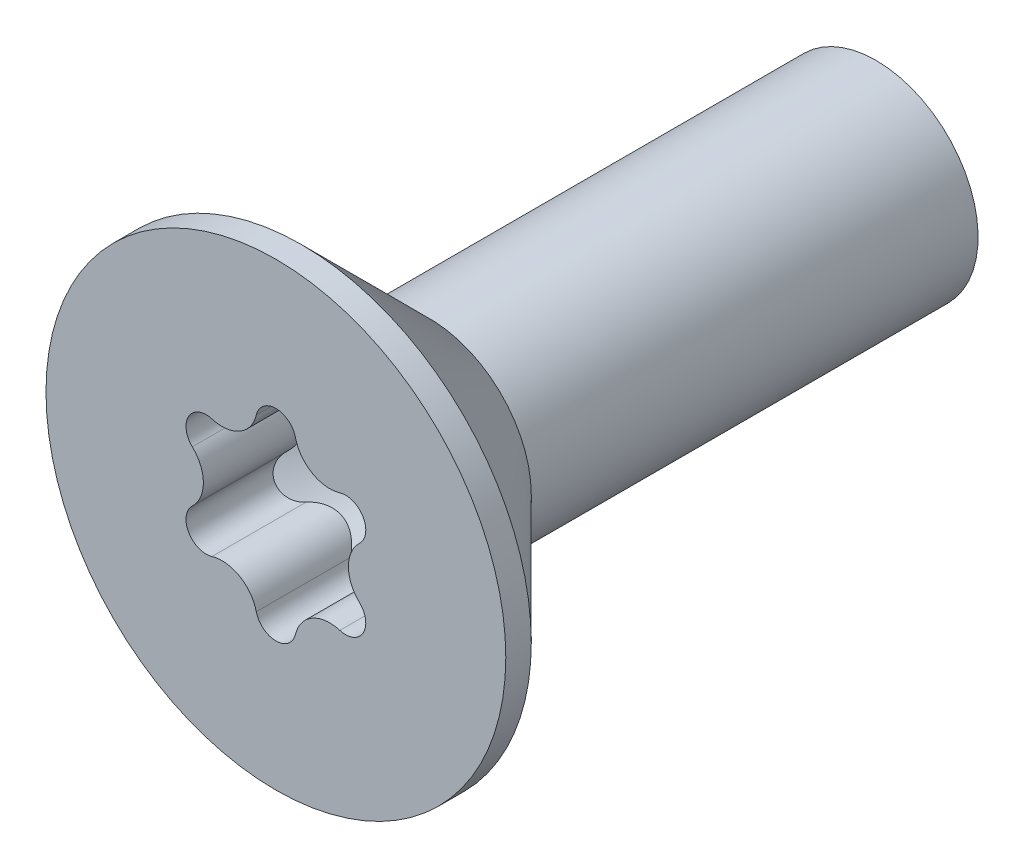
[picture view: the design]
ISO-10303-21;
HEADER;
FILE_DESCRIPTION(('STEP AP214'),'2;1');
FILE_NAME('part.step','',(''),(''),'','','');
FILE_SCHEMA(('AUTOMOTIVE_DESIGN { 1 0 10303 214 1 1 1 1 }'));
ENDSEC;
DATA;
#1=APPLICATION_CONTEXT('core data for automotive mechanical design processes');
#2=APPLICATION_PROTOCOL_DEFINITION('international standard','automotive_design',2000,#1);
#3=PRODUCT_CONTEXT('',#1,'mechanical');
#4=PRODUCT('Part','Part','',(#3));
#5=PRODUCT_RELATED_PRODUCT_CATEGORY('part','',(#4));
#6=PRODUCT_DEFINITION_FORMATION('','',#4);
#7=PRODUCT_DEFINITION_CONTEXT('part definition',#1,'design');
#8=PRODUCT_DEFINITION('design','',#6,#7);
#9=PRODUCT_DEFINITION_SHAPE('','',#8);
#10=(LENGTH_UNIT() NAMED_UNIT(*) SI_UNIT(.MILLI.,.METRE.));
#11=(NAMED_UNIT(*) PLANE_ANGLE_UNIT() SI_UNIT($,.RADIAN.));
#12=(NAMED_UNIT(*) SI_UNIT($,.STERADIAN.) SOLID_ANGLE_UNIT());
#13=UNCERTAINTY_MEASURE_WITH_UNIT(LENGTH_MEASURE(1.E-05),#10,'distance_accuracy_value','');
#14=(GEOMETRIC_REPRESENTATION_CONTEXT(3) GLOBAL_UNCERTAINTY_ASSIGNED_CONTEXT((#13)) GLOBAL_UNIT_ASSIGNED_CONTEXT((#10,
#11,#12)) REPRESENTATION_CONTEXT('',''));
#15=CARTESIAN_POINT('',(0.,0.,0.));
#16=DIRECTION('',(0.,0.,1.));
#17=DIRECTION('',(1.,0.,0.));
#18=AXIS2_PLACEMENT_3D('',#15,#16,#17);
#19=CARTESIAN_POINT('',(0.,0.,-2.87669972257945));
#20=DIRECTION('',(0.,0.,1.));
#21=DIRECTION('',(1.,0.,0.));
#22=AXIS2_PLACEMENT_3D('',#19,#20,#21);
#23=CONICAL_SURFACE('',#22,0.,1.02974425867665);
#24=CARTESIAN_POINT('',(0.,0.,-2.87669972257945));
#25=VERTEX_POINT('',#24);
#26=VERTEX_LOOP('',#25);
#27=FACE_BOUND('',#26,.T.);
#28=CARTESIAN_POINT('',(-0.384291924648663,-1.67134978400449,-1.84624734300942));
#29=CARTESIAN_POINT('',(-0.39260566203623,-1.63624557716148,-1.86565158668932));
#30=CARTESIAN_POINT('',(-0.403779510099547,-1.6013398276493,-1.88448405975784));
#31=CARTESIAN_POINT('',(-0.432157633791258,-1.53253400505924,-1.92005518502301));
#32=CARTESIAN_POINT('',(-0.449412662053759,-1.49864508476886,-1.93677455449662));
#33=CARTESIAN_POINT('',(-0.486363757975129,-1.43917197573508,-1.96402328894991));
#34=CARTESIAN_POINT('',(-0.505018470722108,-1.41321088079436,-1.97512558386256));
#35=CARTESIAN_POINT('',(-0.546368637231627,-1.36355413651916,-1.99422986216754));
#36=CARTESIAN_POINT('',(-0.569051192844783,-1.33985161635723,-2.00224149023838));
#37=CARTESIAN_POINT('',(-0.618391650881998,-1.2952919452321,-2.01447304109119));
#38=CARTESIAN_POINT('',(-0.6450836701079,-1.27446248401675,-2.01865799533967));
#39=CARTESIAN_POINT('',(-0.70148406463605,-1.23683559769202,-2.02256671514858));
#40=CARTESIAN_POINT('',(-0.731191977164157,-1.22003755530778,-2.02229116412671));
#41=CARTESIAN_POINT('',(-0.788409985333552,-1.19301747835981,-2.01765359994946));
#42=CARTESIAN_POINT('',(-0.81569849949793,-1.1822223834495,-2.01383140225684));
#43=CARTESIAN_POINT('',(-0.870881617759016,-1.16428859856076,-2.00322990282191));
#44=CARTESIAN_POINT('',(-0.898776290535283,-1.15715032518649,-1.99645026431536));
#45=CARTESIAN_POINT('',(-0.955959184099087,-1.14617507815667,-1.98005186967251));
#46=CARTESIAN_POINT('',(-0.985245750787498,-1.14252551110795,-1.97030570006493));
#47=CARTESIAN_POINT('',(-1.04329748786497,-1.13893373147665,-1.94874156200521));
#48=CARTESIAN_POINT('',(-1.07206196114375,-1.13899615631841,-1.93692102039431));
#49=CARTESIAN_POINT('',(-1.12719729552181,-1.14246664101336,-1.91242202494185));
#50=CARTESIAN_POINT('',(-1.15361466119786,-1.14569954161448,-1.89982077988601));
#51=CARTESIAN_POINT('',(-1.2053168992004,-1.15501804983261,-1.87366684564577));
#52=CARTESIAN_POINT('',(-1.23060610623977,-1.16109147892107,-1.86011842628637));
#53=CARTESIAN_POINT('',(-1.25528850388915,-1.16848238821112,-1.84624560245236));
#54=B_SPLINE_CURVE_WITH_KNOTS('',3,(#28,#29,#30,#31,#32,#33,#34,#35,#36,#37,#38,#39,#40,#41,#42,
#43,#44,#45,#46,#47,#48,#49,#50,#51,#52,#53),.UNSPECIFIED.,.F.,.F.,(4,2,2,2,2,2,2,2,2,2,2,2,4),
(0.,0.123010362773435,0.247072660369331,0.348194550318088,0.44899827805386,0.550714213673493,
0.652414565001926,0.740798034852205,0.829191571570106,0.922103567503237,1.01513164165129,
1.10329402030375,1.19108182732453),.UNSPECIFIED.);
#55=CARTESIAN_POINT('',(-0.384339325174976,-1.67114978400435,-1.84635807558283));
#56=VERTEX_POINT('',#55);
#57=CARTESIAN_POINT('',(-1.25508850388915,-1.16842251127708,-1.84635807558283));
#58=VERTEX_POINT('',#57);
#59=EDGE_CURVE('E273',#56,#58,#54,.T.);
#60=ORIENTED_EDGE('',*,*,#59,.F.);
#61=CARTESIAN_POINT('',(-0.384386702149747,-1.67094978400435,-1.84646880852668));
#62=CARTESIAN_POINT('',(-0.379134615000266,-1.693214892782,-1.83413548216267));
#63=CARTESIAN_POINT('',(-0.371861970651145,-1.71524756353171,-1.82216290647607));
#64=CARTESIAN_POINT('',(-0.353281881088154,-1.75822712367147,-1.79916664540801));
#65=CARTESIAN_POINT('',(-0.34195446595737,-1.77916804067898,-1.78814799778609));
#66=CARTESIAN_POINT('',(-0.315279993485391,-1.819173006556,-1.76738120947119));
#67=CARTESIAN_POINT('',(-0.299919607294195,-1.83823053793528,-1.75763744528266));
#68=CARTESIAN_POINT('',(-0.265486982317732,-1.87350798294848,-1.73979742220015));
#69=CARTESIAN_POINT('',(-0.246422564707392,-1.88973374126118,-1.73169776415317));
#70=CARTESIAN_POINT('',(-0.207080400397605,-1.9171363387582,-1.71813025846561));
#71=CARTESIAN_POINT('',(-0.187099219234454,-1.92865005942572,-1.71248344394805));
#72=CARTESIAN_POINT('',(-0.1450833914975,-1.9481167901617,-1.7029838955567));
#73=CARTESIAN_POINT('',(-0.123050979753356,-1.95607362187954,-1.69912923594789));
#74=CARTESIAN_POINT('',(-0.0841302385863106,-1.96630367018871,-1.69418586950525));
#75=CARTESIAN_POINT('',(-0.0675498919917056,-1.96954796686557,-1.69262317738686));
#76=CARTESIAN_POINT('',(-0.0340480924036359,-1.97389178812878,-1.69053235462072));
#77=CARTESIAN_POINT('',(-0.0171267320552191,-1.97499188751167,-1.69000394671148));
#78=CARTESIAN_POINT('',(0.0203308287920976,-1.97500972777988,-1.68999526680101));
#79=CARTESIAN_POINT('',(0.0408695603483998,-1.97341291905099,-1.69076212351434));
#80=CARTESIAN_POINT('',(0.081347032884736,-1.96707609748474,-1.69381410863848));
#81=CARTESIAN_POINT('',(0.101285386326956,-1.9623340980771,-1.69610019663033));
#82=CARTESIAN_POINT('',(0.139953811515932,-1.94993158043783,-1.70210810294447));
#83=CARTESIAN_POINT('',(0.158686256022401,-1.94227701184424,-1.70582699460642));
#84=CARTESIAN_POINT('',(0.194519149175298,-1.92436712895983,-1.7145852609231));
#85=CARTESIAN_POINT('',(0.211619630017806,-1.91411186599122,-1.71962460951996));
#86=CARTESIAN_POINT('',(0.244407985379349,-1.89097673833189,-1.73108596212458));
#87=CARTESIAN_POINT('',(0.260023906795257,-1.87801644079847,-1.73755079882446));
#88=CARTESIAN_POINT('',(0.288855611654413,-1.85016598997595,-1.75158347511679));
#89=CARTESIAN_POINT('',(0.302070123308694,-1.83527482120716,-1.75915189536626));
#90=CARTESIAN_POINT('',(0.327033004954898,-1.80256675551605,-1.77596809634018));
#91=CARTESIAN_POINT('',(0.338532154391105,-1.78460661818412,-1.78530649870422));
#92=CARTESIAN_POINT('',(0.358348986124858,-1.74749105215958,-1.80488145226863));
#93=CARTESIAN_POINT('',(0.366668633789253,-1.7283363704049,-1.81511744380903));
#94=CARTESIAN_POINT('',(0.377715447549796,-1.69632628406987,-1.83249007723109));
#95=CARTESIAN_POINT('',(0.381378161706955,-1.68367631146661,-1.83942118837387));
#96=CARTESIAN_POINT('',(0.384386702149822,-1.67094978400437,-1.84646880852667));
#97=B_SPLINE_CURVE_WITH_KNOTS('',3,(#61,#62,#63,#64,#65,#66,#67,#68,#69,#70,#71,#72,#73,#74,#75,
#76,#77,#78,#79,#80,#81,#82,#83,#84,#85,#86,#87,#88,#89,#90,#91,#92,#93,#94,#95,#96),
.UNSPECIFIED.,.F.,.F.,(4,2,2,2,2,2,2,2,2,2,2,2,2,2,2,2,2,4),(0.,0.0779468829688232,
0.156283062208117,0.234881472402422,0.313315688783,0.384149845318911,0.45490771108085,
0.505648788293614,0.556376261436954,0.617904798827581,0.679472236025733,0.7409145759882,
0.802355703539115,0.865983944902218,0.929645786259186,0.999205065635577,1.06872127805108,
1.11329798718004),.UNSPECIFIED.);
#98=CARTESIAN_POINT('',(0.384339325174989,-1.67114978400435,-1.84635807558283));
#99=VERTEX_POINT('',#98);
#100=EDGE_CURVE('E298',#56,#99,#97,.T.);
#101=ORIENTED_EDGE('',*,*,#100,.T.);
#102=CARTESIAN_POINT('',(1.25528850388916,-1.16848238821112,-1.84624560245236));
#103=CARTESIAN_POINT('',(1.22073044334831,-1.15812999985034,-1.86564995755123));
#104=CARTESIAN_POINT('',(1.18491418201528,-1.15035377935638,-1.88448254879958));
#105=CARTESIAN_POINT('',(1.11113735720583,-1.14052670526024,-1.9200539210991));
#106=CARTESIAN_POINT('',(1.07316107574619,-1.13852538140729,-1.93677341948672));
#107=CARTESIAN_POINT('',(1.00318013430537,-1.14078915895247,-1.96402237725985));
#108=CARTESIAN_POINT('',(0.971369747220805,-1.14396395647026,-1.9751247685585));
#109=CARTESIAN_POINT('',(0.90769051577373,-1.15494567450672,-1.99422924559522));
#110=CARTESIAN_POINT('',(0.87582217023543,-1.16273798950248,-2.00224097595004));
#111=CARTESIAN_POINT('',(0.812561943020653,-1.18318807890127,-2.01447273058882));
#112=CARTESIAN_POINT('',(0.781176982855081,-1.19588924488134,-2.01865778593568));
#113=CARTESIAN_POINT('',(0.720390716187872,-1.22591986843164,-2.02256669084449));
#114=CARTESIAN_POINT('',(0.690989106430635,-1.24324861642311,-2.02229122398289));
#115=CARTESIAN_POINT('',(0.638979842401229,-1.27929075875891,-2.01765379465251));
#116=CARTESIAN_POINT('',(0.615986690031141,-1.2975257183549,-2.01383165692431));
#117=CARTESIAN_POINT('',(0.572863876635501,-1.33634874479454,-2.0032302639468));
#118=CARTESIAN_POINT('',(0.552734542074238,-1.35693707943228,-1.99645067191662));
#119=CARTESIAN_POINT('',(0.514638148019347,-1.40097121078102,-1.98005237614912));
#120=CARTESIAN_POINT('',(0.496834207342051,-1.42450927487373,-1.97030626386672));
#121=CARTESIAN_POINT('',(0.464697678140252,-1.47298754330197,-1.94874223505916));
#122=CARTESIAN_POINT('',(0.450369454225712,-1.49792946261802,-1.936921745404));
#123=CARTESIAN_POINT('',(0.425807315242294,-1.54741299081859,-1.91242294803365));
#124=CARTESIAN_POINT('',(0.415398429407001,-1.57190728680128,-1.89982186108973));
#125=CARTESIAN_POINT('',(0.397617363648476,-1.62134146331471,-1.87366825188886));
#126=CARTESIAN_POINT('',(0.390232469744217,-1.64627900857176,-1.8601199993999));
#127=CARTESIAN_POINT('',(0.384291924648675,-1.67134978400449,-1.84624734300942));
#128=B_SPLINE_CURVE_WITH_KNOTS('',3,(#102,#103,#104,#105,#106,#107,#108,#109,#110,#111,#112,
#113,#114,#115,#116,#117,#118,#119,#120,#121,#122,#123,#124,#125,#126,#127),.UNSPECIFIED.,.F.,
.F.,(4,2,2,2,2,2,2,2,2,2,2,2,4),(0.,0.123010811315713,0.247073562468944,0.348195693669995,
0.448999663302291,0.550715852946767,0.652416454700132,0.740799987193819,0.829193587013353,
0.922105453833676,1.01513339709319,1.10329489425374,1.19108182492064),.UNSPECIFIED.);
#129=CARTESIAN_POINT('',(1.25508850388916,-1.16842251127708,-1.84635807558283));
#130=VERTEX_POINT('',#129);
#131=EDGE_CURVE('E305',#130,#99,#128,.T.);
#132=ORIENTED_EDGE('',*,*,#131,.F.);
#133=CARTESIAN_POINT('',(1.25488850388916,-1.16836260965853,-1.84647055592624));
#134=CARTESIAN_POINT('',(1.27679668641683,-1.17494691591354,-1.83413716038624));
#135=CARTESIAN_POINT('',(1.29951386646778,-1.17966514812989,-1.82216451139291));
#136=CARTESIAN_POINT('',(1.34602534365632,-1.18506447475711,-1.79916809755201));
#137=CARTESIAN_POINT('',(1.36982445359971,-1.18572528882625,-1.78814937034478));
#138=CARTESIAN_POINT('',(1.4178071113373,-1.18262735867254,-1.76738241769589));
#139=CARTESIAN_POINT('',(1.44199167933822,-1.17885381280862,-1.75763856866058));
#140=CARTESIAN_POINT('',(1.48975933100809,-1.16667333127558,-1.73979837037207));
#141=CARTESIAN_POINT('',(1.51334356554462,-1.15827609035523,-1.73169862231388));
#142=CARTESIAN_POINT('',(1.55674622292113,-1.13790633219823,-1.71813094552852));
#143=CARTESIAN_POINT('',(1.57670810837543,-1.12635909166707,-1.7124840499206));
#144=CARTESIAN_POINT('',(1.61457495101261,-1.09970587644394,-1.70298434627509));
#145=CARTESIAN_POINT('',(1.63248210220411,-1.0846037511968,-1.6991296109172));
#146=CARTESIAN_POINT('',(1.66079883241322,-1.05601593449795,-1.6941867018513));
#147=CARTESIAN_POINT('',(1.67189581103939,-1.04328295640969,-1.69262425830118));
#148=CARTESIAN_POINT('',(1.69240392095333,-1.01644989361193,-1.69053334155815));
#149=CARTESIAN_POINT('',(1.701815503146,-1.00235017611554,-1.69000459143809));
#150=CARTESIAN_POINT('',(1.7205597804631,-0.969925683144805,-1.68999450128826));
#151=CARTESIAN_POINT('',(1.72944765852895,-0.951341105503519,-1.69076056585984));
#152=CARTESIAN_POINT('',(1.74420148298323,-0.913119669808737,-1.69381096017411));
#153=CARTESIAN_POINT('',(1.75006551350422,-0.893482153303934,-1.69609625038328));
#154=CARTESIAN_POINT('',(1.7586620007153,-0.853793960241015,-1.70210258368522));
#155=CARTESIAN_POINT('',(1.7614007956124,-0.833744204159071,-1.70582070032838));
#156=CARTESIAN_POINT('',(1.76381008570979,-0.793757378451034,-1.71457745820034));
#157=CARTESIAN_POINT('',(1.76348064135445,-0.773820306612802,-1.71961607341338));
#158=CARTESIAN_POINT('',(1.75984250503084,-0.733857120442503,-1.73107593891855));
#159=CARTESIAN_POINT('',(1.75642820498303,-0.713853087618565,-1.73754001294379));
#160=CARTESIAN_POINT('',(1.746728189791,-0.674958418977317,-1.75157120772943));
#161=CARTESIAN_POINT('',(1.74044096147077,-0.656068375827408,-1.75913890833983));
#162=CARTESIAN_POINT('',(1.72459981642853,-0.618095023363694,-1.77595358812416));
#163=CARTESIAN_POINT('',(1.71479725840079,-0.59915588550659,-1.7852911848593));
#164=CARTESIAN_POINT('',(1.69256615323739,-0.563434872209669,-1.80486460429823));
#165=CARTESIAN_POINT('',(1.68013922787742,-0.546651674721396,-1.81509986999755));
#166=CARTESIAN_POINT('',(1.65792040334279,-0.52105132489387,-1.83248965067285));
#167=CARTESIAN_POINT('',(1.64877181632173,-0.511529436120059,-1.83943937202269));
#168=CARTESIAN_POINT('',(1.63922782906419,-0.502538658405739,-1.84650619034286));
#169=B_SPLINE_CURVE_WITH_KNOTS('',3,(#133,#134,#135,#136,#137,#138,#139,#140,#141,#142,#143,
#144,#145,#146,#147,#148,#149,#150,#151,#152,#153,#154,#155,#156,#157,#158,#159,#160,#161,#162,
#163,#164,#165,#166,#167,#168),.UNSPECIFIED.,.F.,.F.,(4,2,2,2,2,2,2,2,2,2,2,2,2,2,2,2,2,4),(0.,
0.0779471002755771,0.156283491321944,0.234882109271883,0.313316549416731,0.384150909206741,
0.454908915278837,0.505635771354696,0.556349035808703,0.617876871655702,0.679443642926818,
0.740885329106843,0.802325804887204,0.865952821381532,0.929613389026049,0.999170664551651,
1.0686850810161,1.11338042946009),.UNSPECIFIED.);
#170=CARTESIAN_POINT('',(1.63942782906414,-0.502727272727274,-1.84635807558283));
#171=VERTEX_POINT('',#170);
#172=EDGE_CURVE('E325',#130,#171,#169,.T.);
#173=ORIENTED_EDGE('',*,*,#172,.T.);
#174=CARTESIAN_POINT('',(1.63962782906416,0.502915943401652,-1.84620994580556));
#175=CARTESIAN_POINT('',(1.61337936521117,0.478164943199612,-1.86561658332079));
#176=CARTESIAN_POINT('',(1.58873286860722,0.451035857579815,-1.88445159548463));
#177=CARTESIAN_POINT('',(1.54332618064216,0.39205719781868,-1.92002802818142));
#178=CARTESIAN_POINT('',(1.52260102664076,0.3601692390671,-1.93675016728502));
#179=CARTESIAN_POINT('',(1.48956476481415,0.298431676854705,-1.96400369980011));
#180=CARTESIAN_POINT('',(1.47640642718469,0.269295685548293,-1.97510806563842));
#181=CARTESIAN_POINT('',(1.45407213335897,0.208656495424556,-1.99421661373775));
#182=CARTESIAN_POINT('',(1.4448837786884,0.177161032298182,-2.00223043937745));
#183=CARTESIAN_POINT('',(1.43095907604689,0.112149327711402,-2.01446636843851));
#184=CARTESIAN_POINT('',(1.42626377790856,0.0786173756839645,-2.01865349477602));
#185=CARTESIAN_POINT('',(1.42187366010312,0.0109566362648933,-2.02256619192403));
#186=CARTESIAN_POINT('',(1.42217807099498,-0.0231720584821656,-2.02229244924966));
#187=CARTESIAN_POINT('',(1.42738373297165,-0.0862371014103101,-2.01765778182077));
#188=CARTESIAN_POINT('',(1.43167769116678,-0.11526805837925,-2.01383687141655));
#189=CARTESIAN_POINT('',(1.44373544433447,-0.172026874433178,-2.00323765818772));
#190=CARTESIAN_POINT('',(1.45149963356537,-0.199754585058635,-1.99645901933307));
#191=CARTESIAN_POINT('',(1.47058354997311,-0.25476506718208,-1.98006275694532));
#192=CARTESIAN_POINT('',(1.48206460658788,-0.281952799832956,-1.97031782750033));
#193=CARTESIAN_POINT('',(1.50797669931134,-0.334023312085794,-1.94875604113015));
#194=CARTESIAN_POINT('',(1.52241140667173,-0.358903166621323,-1.93693660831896));
#195=CARTESIAN_POINT('',(1.55299179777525,-0.404932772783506,-1.91243142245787));
#196=CARTESIAN_POINT('',(1.56901060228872,-0.426208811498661,-1.89982194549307));
#197=CARTESIAN_POINT('',(1.60295496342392,-0.466350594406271,-1.87365033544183));
#198=CARTESIAN_POINT('',(1.62087212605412,-0.485226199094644,-1.86009247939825));
#199=CARTESIAN_POINT('',(1.63962782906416,-0.502915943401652,-1.84620994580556));
#200=B_SPLINE_CURVE_WITH_KNOTS('',3,(#174,#175,#176,#177,#178,#179,#180,#181,#182,#183,#184,
#185,#186,#187,#188,#189,#190,#191,#192,#193,#194,#195,#196,#197,#198,#199),.UNSPECIFIED.,.F.,
.F.,(4,2,2,2,2,2,2,2,2,2,2,2,4),(0.,0.123020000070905,0.247092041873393,0.348219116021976,
0.449028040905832,0.550749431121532,0.652455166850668,0.740839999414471,0.829234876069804,
0.922144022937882,1.01516936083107,1.10338995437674,1.19123556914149),.UNSPECIFIED.);
#201=CARTESIAN_POINT('',(1.63942782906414,0.502727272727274,-1.84635807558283));
#202=VERTEX_POINT('',#201);
#203=EDGE_CURVE('E368',#202,#171,#200,.T.);
#204=ORIENTED_EDGE('',*,*,#203,.F.);
#205=CARTESIAN_POINT('',(1.63922782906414,0.502538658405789,-1.84650619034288));
#206=CARTESIAN_POINT('',(1.65588737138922,0.518217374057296,-1.83417139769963));
#207=CARTESIAN_POINT('',(1.67133549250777,0.535530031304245,-1.82219726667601));
#208=CARTESIAN_POINT('',(1.69927425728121,0.573107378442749,-1.79919773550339));
#209=CARTESIAN_POINT('',(1.71174974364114,0.593386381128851,-1.78817737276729));
#210=CARTESIAN_POINT('',(1.73306560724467,0.636487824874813,-1.76740703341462));
#211=CARTESIAN_POINT('',(1.74189367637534,0.659318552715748,-1.75766143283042));
#212=CARTESIAN_POINT('',(1.7552363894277,0.706776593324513,-1.73981766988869));
#213=CARTESIAN_POINT('',(1.759760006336,0.731400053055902,-1.73171610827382));
#214=CARTESIAN_POINT('',(1.76382745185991,0.779173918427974,-1.71814501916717));
#215=CARTESIAN_POINT('',(1.7638113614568,0.802235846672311,-1.71249651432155));
#216=CARTESIAN_POINT('',(1.75966845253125,0.848358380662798,-1.70299361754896));
#217=CARTESIAN_POINT('',(1.75554606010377,0.871418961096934,-1.69913730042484));
#218=CARTESIAN_POINT('',(1.74494913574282,0.910246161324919,-1.69419084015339));
#219=CARTESIAN_POINT('',(1.73946935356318,0.926231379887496,-1.69262685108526));
#220=CARTESIAN_POINT('',(1.72648083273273,0.95742476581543,-1.69053386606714));
#221=CARTESIAN_POINT('',(1.71897263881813,0.972633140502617,-1.69000459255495));
#222=CARTESIAN_POINT('',(1.70026011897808,1.00508572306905,-1.68999450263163));
#223=CARTESIAN_POINT('',(1.68860933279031,1.0220751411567,-1.69076057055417));
#224=CARTESIAN_POINT('',(1.66288550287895,1.05396303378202,-1.69381097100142));
#225=CARTESIAN_POINT('',(1.64881093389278,1.06886018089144,-1.69609626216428));
#226=CARTESIAN_POINT('',(1.61873819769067,1.09614904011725,-1.70210259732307));
#227=CARTESIAN_POINT('',(1.602743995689,1.10854577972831,-1.7058207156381));
#228=CARTESIAN_POINT('',(1.56931902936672,1.13062569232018,-1.71457747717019));
#229=CARTESIAN_POINT('',(1.55188829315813,1.14030891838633,-1.71961609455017));
#230=CARTESIAN_POINT('',(1.51546008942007,1.1571397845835,-1.73107596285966));
#231=CARTESIAN_POINT('',(1.49642894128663,1.16418492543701,-1.7375400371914));
#232=CARTESIAN_POINT('',(1.45789515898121,1.17523179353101,-1.7515712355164));
#233=CARTESIAN_POINT('',(1.43839228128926,1.17923191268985,-1.75913893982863));
#234=CARTESIAN_POINT('',(1.39758579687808,1.18449974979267,-1.77595363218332));
#235=CARTESIAN_POINT('',(1.37628272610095,1.18548004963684,-1.7852912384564));
#236=CARTESIAN_POINT('',(1.33423185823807,1.18408783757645,-1.8048646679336));
#237=CARTESIAN_POINT('',(1.31348372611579,1.18171739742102,-1.8150999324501));
#238=CARTESIAN_POINT('',(1.28022570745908,1.17527974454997,-1.83247825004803));
#239=CARTESIAN_POINT('',(1.26742645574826,1.17212417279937,-1.83941603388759));
#240=CARTESIAN_POINT('',(1.25488850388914,1.1683626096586,-1.84647055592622));
#241=B_SPLINE_CURVE_WITH_KNOTS('',3,(#205,#206,#207,#208,#209,#210,#211,#212,#213,#214,#215,
#216,#217,#218,#219,#220,#221,#222,#223,#224,#225,#226,#227,#228,#229,#230,#231,#232,#233,#234,
#235,#236,#237,#238,#239,#240),.UNSPECIFIED.,.F.,.F.,(4,2,2,2,2,2,2,2,2,2,2,2,2,2,2,2,2,4),(0.,
0.0779514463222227,0.156292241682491,0.234895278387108,0.31333409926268,0.384171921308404,
0.454933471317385,0.505685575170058,0.556424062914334,0.617951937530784,0.679518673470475,
0.740960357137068,0.802400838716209,0.866027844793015,0.929688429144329,0.999245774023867,
1.06876013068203,1.11338033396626),.UNSPECIFIED.);
#242=CARTESIAN_POINT('',(1.25508850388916,1.16842251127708,-1.84635807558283));
#243=VERTEX_POINT('',#242);
#244=EDGE_CURVE('E380',#202,#243,#241,.T.);
#245=ORIENTED_EDGE('',*,*,#244,.T.);
#246=CARTESIAN_POINT('',(0.384291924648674,1.67134978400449,-1.84624734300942));
#247=CARTESIAN_POINT('',(0.392605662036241,1.63624557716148,-1.86565158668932));
#248=CARTESIAN_POINT('',(0.403779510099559,1.6013398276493,-1.88448405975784));
#249=CARTESIAN_POINT('',(0.432157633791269,1.53253400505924,-1.92005518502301));
#250=CARTESIAN_POINT('',(0.44941266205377,1.49864508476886,-1.93677455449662));
#251=CARTESIAN_POINT('',(0.48636375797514,1.43917197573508,-1.96402328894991));
#252=CARTESIAN_POINT('',(0.505018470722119,1.41321088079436,-1.97512558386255));
#253=CARTESIAN_POINT('',(0.546368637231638,1.36355413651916,-1.99422986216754));
#254=CARTESIAN_POINT('',(0.569051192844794,1.33985161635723,-2.00224149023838));
#255=CARTESIAN_POINT('',(0.618391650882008,1.2952919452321,-2.01447304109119));
#256=CARTESIAN_POINT('',(0.64508367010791,1.27446248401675,-2.01865799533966));
#257=CARTESIAN_POINT('',(0.70148406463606,1.23683559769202,-2.02256671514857));
#258=CARTESIAN_POINT('',(0.731191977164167,1.22003755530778,-2.02229116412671));
#259=CARTESIAN_POINT('',(0.788409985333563,1.19301747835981,-2.01765359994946));
#260=CARTESIAN_POINT('',(0.81569849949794,1.1822223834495,-2.01383140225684));
#261=CARTESIAN_POINT('',(0.870881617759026,1.16428859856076,-2.00322990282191));
#262=CARTESIAN_POINT('',(0.898776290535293,1.15715032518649,-1.99645026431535));
#263=CARTESIAN_POINT('',(0.955959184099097,1.14617507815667,-1.98005186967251));
#264=CARTESIAN_POINT('',(0.985245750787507,1.14252551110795,-1.97030570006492));
#265=CARTESIAN_POINT('',(1.04329748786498,1.13893373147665,-1.9487415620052));
#266=CARTESIAN_POINT('',(1.07206196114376,1.13899615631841,-1.93692102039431));
#267=CARTESIAN_POINT('',(1.12719729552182,1.14246664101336,-1.91242202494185));
#268=CARTESIAN_POINT('',(1.15361466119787,1.14569954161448,-1.89982077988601));
#269=CARTESIAN_POINT('',(1.20531689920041,1.15501804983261,-1.87366684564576));
#270=CARTESIAN_POINT('',(1.23060610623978,1.16109147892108,-1.86011842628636));
#271=CARTESIAN_POINT('',(1.25528850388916,1.16848238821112,-1.84624560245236));
#272=B_SPLINE_CURVE_WITH_KNOTS('',3,(#246,#247,#248,#249,#250,#251,#252,#253,#254,#255,#256,
#257,#258,#259,#260,#261,#262,#263,#264,#265,#266,#267,#268,#269,#270,#271),.UNSPECIFIED.,.F.,
.F.,(4,2,2,2,2,2,2,2,2,2,2,2,4),(0.,0.123010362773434,0.24707266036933,0.348194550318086,
0.448998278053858,0.550714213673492,0.652414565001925,0.740798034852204,0.829191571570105,
0.922103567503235,1.01513164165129,1.10329402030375,1.19108182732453),.UNSPECIFIED.);
#273=CARTESIAN_POINT('',(0.384339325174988,1.67114978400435,-1.84635807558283));
#274=VERTEX_POINT('',#273);
#275=EDGE_CURVE('E399',#274,#243,#272,.T.);
#276=ORIENTED_EDGE('',*,*,#275,.F.);
#277=CARTESIAN_POINT('',(0.384386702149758,1.67094978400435,-1.84646880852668));
#278=CARTESIAN_POINT('',(0.379134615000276,1.693214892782,-1.83413548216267));
#279=CARTESIAN_POINT('',(0.371861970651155,1.71524756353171,-1.82216290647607));
#280=CARTESIAN_POINT('',(0.353281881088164,1.75822712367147,-1.79916664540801));
#281=CARTESIAN_POINT('',(0.341954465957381,1.77916804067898,-1.78814799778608));
#282=CARTESIAN_POINT('',(0.315279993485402,1.819173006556,-1.76738120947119));
#283=CARTESIAN_POINT('',(0.299919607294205,1.83823053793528,-1.75763744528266));
#284=CARTESIAN_POINT('',(0.265486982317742,1.87350798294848,-1.73979742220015));
#285=CARTESIAN_POINT('',(0.246422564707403,1.88973374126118,-1.73169776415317));
#286=CARTESIAN_POINT('',(0.207080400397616,1.9171363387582,-1.71813025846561));
#287=CARTESIAN_POINT('',(0.187099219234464,1.92865005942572,-1.71248344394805));
#288=CARTESIAN_POINT('',(0.14508339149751,1.9481167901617,-1.7029838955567));
#289=CARTESIAN_POINT('',(0.123050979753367,1.95607362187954,-1.69912923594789));
#290=CARTESIAN_POINT('',(0.0841302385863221,1.96630367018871,-1.69418586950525));
#291=CARTESIAN_POINT('',(0.0675498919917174,1.96954796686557,-1.69262317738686));
#292=CARTESIAN_POINT('',(0.0340480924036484,1.97389178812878,-1.69053235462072));
#293=CARTESIAN_POINT('',(0.0171267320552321,1.97499188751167,-1.69000394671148));
#294=CARTESIAN_POINT('',(-0.0203308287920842,1.97500972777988,-1.68999526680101));
#295=CARTESIAN_POINT('',(-0.0408695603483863,1.97341291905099,-1.69076212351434));
#296=CARTESIAN_POINT('',(-0.0813470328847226,1.96707609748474,-1.69381410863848));
#297=CARTESIAN_POINT('',(-0.101285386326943,1.9623340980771,-1.69610019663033));
#298=CARTESIAN_POINT('',(-0.139953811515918,1.94993158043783,-1.70210810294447));
#299=CARTESIAN_POINT('',(-0.158686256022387,1.94227701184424,-1.70582699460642));
#300=CARTESIAN_POINT('',(-0.194519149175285,1.92436712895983,-1.7145852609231));
#301=CARTESIAN_POINT('',(-0.211619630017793,1.91411186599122,-1.71962460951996));
#302=CARTESIAN_POINT('',(-0.244407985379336,1.89097673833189,-1.73108596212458));
#303=CARTESIAN_POINT('',(-0.260023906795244,1.87801644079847,-1.73755079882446));
#304=CARTESIAN_POINT('',(-0.2888556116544,1.85016598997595,-1.75158347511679));
#305=CARTESIAN_POINT('',(-0.302070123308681,1.83527482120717,-1.75915189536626));
#306=CARTESIAN_POINT('',(-0.327033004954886,1.80256675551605,-1.77596809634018));
#307=CARTESIAN_POINT('',(-0.338532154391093,1.78460661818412,-1.78530649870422));
#308=CARTESIAN_POINT('',(-0.358348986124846,1.74749105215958,-1.80488145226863));
#309=CARTESIAN_POINT('',(-0.366668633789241,1.7283363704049,-1.81511744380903));
#310=CARTESIAN_POINT('',(-0.377715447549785,1.69632628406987,-1.83249007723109));
#311=CARTESIAN_POINT('',(-0.381378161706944,1.68367631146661,-1.83942118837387));
#312=CARTESIAN_POINT('',(-0.384386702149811,1.67094978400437,-1.84646880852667));
#313=B_SPLINE_CURVE_WITH_KNOTS('',3,(#277,#278,#279,#280,#281,#282,#283,#284,#285,#286,#287,
#288,#289,#290,#291,#292,#293,#294,#295,#296,#297,#298,#299,#300,#301,#302,#303,#304,#305,#306,
#307,#308,#309,#310,#311,#312),.UNSPECIFIED.,.F.,.F.,(4,2,2,2,2,2,2,2,2,2,2,2,2,2,2,2,2,4),(0.,
0.0779468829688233,0.156283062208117,0.234881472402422,0.313315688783,0.384149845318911,
0.45490771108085,0.505648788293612,0.556376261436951,0.617904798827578,0.67947223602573,
0.740914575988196,0.802355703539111,0.865983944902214,0.929645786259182,0.999205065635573,
1.06872127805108,1.11329798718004),.UNSPECIFIED.);
#314=CARTESIAN_POINT('',(-0.384339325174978,1.67114978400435,-1.84635807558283));
#315=VERTEX_POINT('',#314);
#316=EDGE_CURVE('E408',#274,#315,#313,.T.);
#317=ORIENTED_EDGE('',*,*,#316,.T.);
#318=CARTESIAN_POINT('',(-1.25528850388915,1.16848238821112,-1.84624560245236));
#319=CARTESIAN_POINT('',(-1.2207304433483,1.15812999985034,-1.86564995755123));
#320=CARTESIAN_POINT('',(-1.18491418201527,1.15035377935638,-1.88448254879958));
#321=CARTESIAN_POINT('',(-1.11113735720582,1.14052670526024,-1.9200539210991));
#322=CARTESIAN_POINT('',(-1.07316107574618,1.13852538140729,-1.93677341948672));
#323=CARTESIAN_POINT('',(-1.00318013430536,1.14078915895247,-1.96402237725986));
#324=CARTESIAN_POINT('',(-0.971369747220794,1.14396395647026,-1.9751247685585));
#325=CARTESIAN_POINT('',(-0.907690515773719,1.15494567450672,-1.99422924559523));
#326=CARTESIAN_POINT('',(-0.87582217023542,1.16273798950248,-2.00224097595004));
#327=CARTESIAN_POINT('',(-0.812561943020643,1.18318807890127,-2.01447273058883));
#328=CARTESIAN_POINT('',(-0.78117698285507,1.19588924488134,-2.01865778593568));
#329=CARTESIAN_POINT('',(-0.720390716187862,1.22591986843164,-2.02256669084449));
#330=CARTESIAN_POINT('',(-0.690989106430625,1.24324861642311,-2.02229122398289));
#331=CARTESIAN_POINT('',(-0.638979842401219,1.27929075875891,-2.01765379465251));
#332=CARTESIAN_POINT('',(-0.615986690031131,1.2975257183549,-2.01383165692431));
#333=CARTESIAN_POINT('',(-0.572863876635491,1.33634874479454,-2.0032302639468));
#334=CARTESIAN_POINT('',(-0.552734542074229,1.35693707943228,-1.99645067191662));
#335=CARTESIAN_POINT('',(-0.514638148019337,1.40097121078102,-1.98005237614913));
#336=CARTESIAN_POINT('',(-0.496834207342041,1.42450927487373,-1.97030626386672));
#337=CARTESIAN_POINT('',(-0.464697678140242,1.47298754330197,-1.94874223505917));
#338=CARTESIAN_POINT('',(-0.450369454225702,1.49792946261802,-1.93692174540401));
#339=CARTESIAN_POINT('',(-0.425807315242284,1.54741299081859,-1.91242294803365));
#340=CARTESIAN_POINT('',(-0.41539842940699,1.57190728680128,-1.89982186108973));
#341=CARTESIAN_POINT('',(-0.397617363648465,1.6213414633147,-1.87366825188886));
#342=CARTESIAN_POINT('',(-0.390232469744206,1.64627900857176,-1.8601199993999));
#343=CARTESIAN_POINT('',(-0.384291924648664,1.67134978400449,-1.84624734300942));
#344=B_SPLINE_CURVE_WITH_KNOTS('',3,(#318,#319,#320,#321,#322,#323,#324,#325,#326,#327,#328,
#329,#330,#331,#332,#333,#334,#335,#336,#337,#338,#339,#340,#341,#342,#343),.UNSPECIFIED.,.F.,
.F.,(4,2,2,2,2,2,2,2,2,2,2,2,4),(0.,0.123010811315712,0.247073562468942,0.348195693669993,
0.448999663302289,0.550715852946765,0.65241645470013,0.740799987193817,0.82919358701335,
0.922105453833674,1.01513339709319,1.10329489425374,1.19108182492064),.UNSPECIFIED.);
#345=CARTESIAN_POINT('',(-1.25508850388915,1.16842251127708,-1.84635807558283));
#346=VERTEX_POINT('',#345);
#347=EDGE_CURVE('E424',#346,#315,#344,.T.);
#348=ORIENTED_EDGE('',*,*,#347,.F.);
#349=CARTESIAN_POINT('',(-1.25488850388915,1.16836260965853,-1.84647055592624));
#350=CARTESIAN_POINT('',(-1.27679668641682,1.17494691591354,-1.83413716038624));
#351=CARTESIAN_POINT('',(-1.29951386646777,1.17966514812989,-1.82216451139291));
#352=CARTESIAN_POINT('',(-1.34602534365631,1.18506447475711,-1.79916809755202));
#353=CARTESIAN_POINT('',(-1.36982445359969,1.18572528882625,-1.78814937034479));
#354=CARTESIAN_POINT('',(-1.41780711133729,1.18262735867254,-1.7673824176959));
#355=CARTESIAN_POINT('',(-1.44199167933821,1.17885381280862,-1.75763856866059));
#356=CARTESIAN_POINT('',(-1.48975933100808,1.16667333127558,-1.73979837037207));
#357=CARTESIAN_POINT('',(-1.51334356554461,1.15827609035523,-1.73169862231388));
#358=CARTESIAN_POINT('',(-1.55674622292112,1.13790633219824,-1.71813094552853));
#359=CARTESIAN_POINT('',(-1.57670810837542,1.12635909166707,-1.71248404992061));
#360=CARTESIAN_POINT('',(-1.6145749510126,1.09970587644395,-1.70298434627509));
#361=CARTESIAN_POINT('',(-1.6324821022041,1.0846037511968,-1.69912961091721));
#362=CARTESIAN_POINT('',(-1.66079883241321,1.05601593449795,-1.69418670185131));
#363=CARTESIAN_POINT('',(-1.67189581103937,1.04328295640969,-1.69262425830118));
#364=CARTESIAN_POINT('',(-1.69240392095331,1.01644989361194,-1.69053334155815));
#365=CARTESIAN_POINT('',(-1.70181550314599,1.00235017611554,-1.6900045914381));
#366=CARTESIAN_POINT('',(-1.72055978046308,0.969925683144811,-1.68999450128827));
#367=CARTESIAN_POINT('',(-1.72944765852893,0.951341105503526,-1.69076056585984));
#368=CARTESIAN_POINT('',(-1.74420148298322,0.913119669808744,-1.69381096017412));
#369=CARTESIAN_POINT('',(-1.75006551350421,0.893482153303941,-1.69609625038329));
#370=CARTESIAN_POINT('',(-1.75866200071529,0.853793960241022,-1.70210258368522));
#371=CARTESIAN_POINT('',(-1.76140079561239,0.833744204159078,-1.70582070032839));
#372=CARTESIAN_POINT('',(-1.76381008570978,0.793757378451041,-1.71457745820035));
#373=CARTESIAN_POINT('',(-1.76348064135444,0.773820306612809,-1.71961607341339));
#374=CARTESIAN_POINT('',(-1.75984250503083,0.73385712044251,-1.73107593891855));
#375=CARTESIAN_POINT('',(-1.75642820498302,0.713853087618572,-1.73754001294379));
#376=CARTESIAN_POINT('',(-1.74672818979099,0.674958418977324,-1.75157120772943));
#377=CARTESIAN_POINT('',(-1.74044096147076,0.656068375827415,-1.75913890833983));
#378=CARTESIAN_POINT('',(-1.72459981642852,0.618095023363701,-1.77595358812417));
#379=CARTESIAN_POINT('',(-1.71479725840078,0.599155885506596,-1.7852911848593));
#380=CARTESIAN_POINT('',(-1.69256615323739,0.563434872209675,-1.80486460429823));
#381=CARTESIAN_POINT('',(-1.68013922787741,0.546651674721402,-1.81509986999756));
#382=CARTESIAN_POINT('',(-1.65792040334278,0.521051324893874,-1.83248965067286));
#383=CARTESIAN_POINT('',(-1.64877181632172,0.511529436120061,-1.83943937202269));
#384=CARTESIAN_POINT('',(-1.63922782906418,0.50253865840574,-1.84650619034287));
#385=B_SPLINE_CURVE_WITH_KNOTS('',3,(#349,#350,#351,#352,#353,#354,#355,#356,#357,#358,#359,
#360,#361,#362,#363,#364,#365,#366,#367,#368,#369,#370,#371,#372,#373,#374,#375,#376,#377,#378,
#379,#380,#381,#382,#383,#384),.UNSPECIFIED.,.F.,.F.,(4,2,2,2,2,2,2,2,2,2,2,2,2,2,2,2,2,4),(0.,
0.0779471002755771,0.156283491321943,0.234882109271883,0.31331654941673,0.384150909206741,
0.454908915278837,0.505635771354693,0.556349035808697,0.617876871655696,0.679443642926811,
0.740885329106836,0.802325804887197,0.865952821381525,0.929613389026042,0.999170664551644,
1.06868508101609,1.11338042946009),.UNSPECIFIED.);
#386=CARTESIAN_POINT('',(-1.63942782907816,0.502727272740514,-1.84635807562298));
#387=VERTEX_POINT('',#386);
#388=EDGE_CURVE('E197',#346,#387,#385,.T.);
#389=ORIENTED_EDGE('',*,*,#388,.T.);
#390=CARTESIAN_POINT('',(-1.63962782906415,-0.502915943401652,-1.84620994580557));
#391=CARTESIAN_POINT('',(-1.61337936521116,-0.478164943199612,-1.86561658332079));
#392=CARTESIAN_POINT('',(-1.58873286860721,-0.451035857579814,-1.88445159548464));
#393=CARTESIAN_POINT('',(-1.54332618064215,-0.392057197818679,-1.92002802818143));
#394=CARTESIAN_POINT('',(-1.52260102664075,-0.3601692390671,-1.93675016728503));
#395=CARTESIAN_POINT('',(-1.48956476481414,-0.298431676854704,-1.96400369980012));
#396=CARTESIAN_POINT('',(-1.47640642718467,-0.269295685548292,-1.97510806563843));
#397=CARTESIAN_POINT('',(-1.45407213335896,-0.208656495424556,-1.99421661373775));
#398=CARTESIAN_POINT('',(-1.44488377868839,-0.177161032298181,-2.00223043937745));
#399=CARTESIAN_POINT('',(-1.43095907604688,-0.112149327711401,-2.01446636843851));
#400=CARTESIAN_POINT('',(-1.42626377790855,-0.0786173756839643,-2.01865349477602));
#401=CARTESIAN_POINT('',(-1.42187366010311,-0.0109566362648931,-2.02256619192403));
#402=CARTESIAN_POINT('',(-1.42217807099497,0.0231720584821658,-2.02229244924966));
#403=CARTESIAN_POINT('',(-1.42738373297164,0.0862371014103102,-2.01765778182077));
#404=CARTESIAN_POINT('',(-1.43167769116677,0.11526805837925,-2.01383687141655));
#405=CARTESIAN_POINT('',(-1.44373544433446,0.172026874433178,-2.00323765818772));
#406=CARTESIAN_POINT('',(-1.45149963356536,0.199754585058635,-1.99645901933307));
#407=CARTESIAN_POINT('',(-1.47058354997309,0.25476506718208,-1.98006275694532));
#408=CARTESIAN_POINT('',(-1.48206460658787,0.281952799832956,-1.97031782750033));
#409=CARTESIAN_POINT('',(-1.50797669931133,0.334023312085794,-1.94875604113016));
#410=CARTESIAN_POINT('',(-1.52241140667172,0.358903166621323,-1.93693660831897));
#411=CARTESIAN_POINT('',(-1.55299179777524,0.404932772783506,-1.91243142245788));
#412=CARTESIAN_POINT('',(-1.56901060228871,0.426208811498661,-1.89982194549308));
#413=CARTESIAN_POINT('',(-1.60295496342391,0.466350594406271,-1.87365033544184));
#414=CARTESIAN_POINT('',(-1.62087212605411,0.485226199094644,-1.86009247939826));
#415=CARTESIAN_POINT('',(-1.63962782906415,0.502915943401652,-1.84620994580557));
#416=B_SPLINE_CURVE_WITH_KNOTS('',3,(#390,#391,#392,#393,#394,#395,#396,#397,#398,#399,#400,
#401,#402,#403,#404,#405,#406,#407,#408,#409,#410,#411,#412,#413,#414,#415),.UNSPECIFIED.,.F.,
.F.,(4,2,2,2,2,2,2,2,2,2,2,2,4),(0.,0.123020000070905,0.247092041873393,0.348219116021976,
0.449028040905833,0.550749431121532,0.652455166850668,0.74083999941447,0.829234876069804,
0.922144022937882,1.01516936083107,1.10338995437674,1.19123556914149),.UNSPECIFIED.);
#417=CARTESIAN_POINT('',(-1.63942782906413,-0.502727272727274,-1.84635807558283));
#418=VERTEX_POINT('',#417);
#419=EDGE_CURVE('E274',#418,#387,#416,.T.);
#420=ORIENTED_EDGE('',*,*,#419,.F.);
#421=CARTESIAN_POINT('',(-1.63922782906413,-0.502538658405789,-1.84650619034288));
#422=CARTESIAN_POINT('',(-1.65588736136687,-0.518217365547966,-1.83417140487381));
#423=CARTESIAN_POINT('',(-1.6713354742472,-0.535530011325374,-1.82219728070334));
#424=CARTESIAN_POINT('',(-1.69927424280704,-0.573107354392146,-1.79919774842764));
#425=CARTESIAN_POINT('',(-1.71174973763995,-0.593386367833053,-1.78817737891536));
#426=CARTESIAN_POINT('',(-1.73306562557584,-0.636487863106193,-1.76740701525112));
#427=CARTESIAN_POINT('',(-1.74189370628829,-0.659318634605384,-1.7576613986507));
#428=CARTESIAN_POINT('',(-1.75523640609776,-0.706776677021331,-1.739817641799));
#429=CARTESIAN_POINT('',(-1.75976001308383,-0.731400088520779,-1.73171609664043));
#430=CARTESIAN_POINT('',(-1.76382743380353,-0.77917374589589,-1.71814506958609));
#431=CARTESIAN_POINT('',(-1.76381135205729,-0.80223550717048,-1.7124966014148));
#432=CARTESIAN_POINT('',(-1.75966852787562,-0.84835798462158,-1.7029936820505));
#433=CARTESIAN_POINT('',(-1.75554614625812,-0.871418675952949,-1.69913733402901));
#434=CARTESIAN_POINT('',(-1.74492899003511,-0.910319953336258,-1.69418144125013));
#435=CARTESIAN_POINT('',(-1.7394194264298,-0.926376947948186,-1.69261261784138));
#436=CARTESIAN_POINT('',(-1.72635326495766,-0.957705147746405,-1.69051957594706));
#437=CARTESIAN_POINT('',(-1.71879724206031,-0.972976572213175,-1.68999506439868));
#438=CARTESIAN_POINT('',(-1.70004674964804,-1.00540743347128,-1.69000600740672));
#439=CARTESIAN_POINT('',(-1.68842524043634,-1.02232223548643,-1.6907778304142));
#440=CARTESIAN_POINT('',(-1.66277985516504,-1.05407486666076,-1.69382812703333));
#441=CARTESIAN_POINT('',(-1.64875450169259,-1.0689114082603,-1.69610752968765));
#442=CARTESIAN_POINT('',(-1.61873835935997,-1.09614887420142,-1.70210256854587));
#443=CARTESIAN_POINT('',(-1.60274424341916,-1.10854558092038,-1.70582065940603));
#444=CARTESIAN_POINT('',(-1.56931927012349,-1.13062556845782,-1.71457740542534));
#445=CARTESIAN_POINT('',(-1.55188841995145,-1.14030886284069,-1.71961605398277));
#446=CARTESIAN_POINT('',(-1.51546006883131,-1.15713979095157,-1.73107597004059));
#447=CARTESIAN_POINT('',(-1.49642889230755,-1.16418494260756,-1.73754005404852));
#448=CARTESIAN_POINT('',(-1.45789510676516,-1.17523180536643,-1.75157125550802));
#449=CARTESIAN_POINT('',(-1.43839225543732,-1.1792319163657,-1.75913895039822));
#450=CARTESIAN_POINT('',(-1.39758580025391,-1.18449974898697,-1.77595363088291));
#451=CARTESIAN_POINT('',(-1.37628273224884,-1.18548004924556,-1.78529123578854));
#452=CARTESIAN_POINT('',(-1.33423186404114,-1.18408783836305,-1.80486466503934));
#453=CARTESIAN_POINT('',(-1.31348372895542,-1.1817173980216,-1.815099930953));
#454=CARTESIAN_POINT('',(-1.28022570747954,-1.17527974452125,-1.83247825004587));
#455=CARTESIAN_POINT('',(-1.2674264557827,-1.17212417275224,-1.83941603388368));
#456=CARTESIAN_POINT('',(-1.25488850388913,-1.1683626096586,-1.84647055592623));
#457=B_SPLINE_CURVE_WITH_KNOTS('',3,(#421,#422,#423,#424,#425,#426,#427,#428,#429,#430,#431,
#432,#433,#434,#435,#436,#437,#438,#439,#440,#441,#442,#443,#444,#445,#446,#447,#448,#449,#450,
#451,#452,#453,#454,#455,#456),.UNSPECIFIED.,.F.,.F.,(4,2,2,2,2,2,2,2,2,2,2,2,2,2,2,2,2,4),(0.,
0.0779514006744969,0.156292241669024,0.234895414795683,0.313334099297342,0.384171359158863,
0.454933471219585,0.505916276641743,0.556884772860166,0.618183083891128,0.679519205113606,
0.740960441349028,0.802401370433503,0.866028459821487,0.929688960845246,0.99924629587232,
1.06876066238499,1.11338086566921),.UNSPECIFIED.);
#458=EDGE_CURVE('E270',#418,#58,#457,.T.);
#459=ORIENTED_EDGE('',*,*,#458,.T.);
#460=EDGE_LOOP('',(#60,#101,#132,#173,#204,#245,#276,#317,#348,#389,#420,#459));
#461=FACE_BOUND('',#460,.T.);
#462=ADVANCED_FACE('F182',(#27,#461),#23,.F.);
#463=CARTESIAN_POINT('',(0.,0.,0.));
#464=DIRECTION('',(0.,0.,1.));
#465=DIRECTION('',(1.,0.,0.));
#466=AXIS2_PLACEMENT_3D('',#463,#464,#465);
#467=PLANE('',#466);
#468=CARTESIAN_POINT('',(-1.36832013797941,0.790000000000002,0.));
#469=DIRECTION('',(0.,0.,1.));
#470=DIRECTION('',(1.,0.,0.));
#471=AXIS2_PLACEMENT_3D('',#468,#469,#470);
#472=CIRCLE('',#471,0.395);
#473=CARTESIAN_POINT('',(-1.25508850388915,1.16842251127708,0.));
#474=VERTEX_POINT('',#473);
#475=CARTESIAN_POINT('',(-1.63942782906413,0.502727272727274,0.));
#476=VERTEX_POINT('',#475);
#477=EDGE_CURVE('E493',#474,#476,#472,.T.);
#478=ORIENTED_EDGE('',*,*,#477,.F.);
#479=CARTESIAN_POINT('',(-1.0569331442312,1.83066190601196,0.));
#480=DIRECTION('',(0.,0.,1.));
#481=DIRECTION('',(1.,0.,0.));
#482=AXIS2_PLACEMENT_3D('',#479,#480,#481);
#483=CIRCLE('',#482,0.69125);
#484=CARTESIAN_POINT('',(-0.384339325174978,1.67114978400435,0.));
#485=VERTEX_POINT('',#484);
#486=EDGE_CURVE('E431',#474,#485,#483,.T.);
#487=ORIENTED_EDGE('',*,*,#486,.T.);
#488=CARTESIAN_POINT('',(0.,1.58,0.));
#489=DIRECTION('',(0.,0.,1.));
#490=DIRECTION('',(1.,0.,0.));
#491=AXIS2_PLACEMENT_3D('',#488,#489,#490);
#492=CIRCLE('',#491,0.395);
#493=CARTESIAN_POINT('',(0.384339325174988,1.67114978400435,0.));
#494=VERTEX_POINT('',#493);
#495=EDGE_CURVE('E508',#494,#485,#492,.T.);
#496=ORIENTED_EDGE('',*,*,#495,.F.);
#497=CARTESIAN_POINT('',(1.05693314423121,1.83066190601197,0.));
#498=DIRECTION('',(0.,0.,1.));
#499=DIRECTION('',(1.,0.,0.));
#500=AXIS2_PLACEMENT_3D('',#497,#498,#499);
#501=CIRCLE('',#500,0.69125);
#502=CARTESIAN_POINT('',(1.25508850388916,1.16842251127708,0.));
#503=VERTEX_POINT('',#502);
#504=EDGE_CURVE('E406',#494,#503,#501,.T.);
#505=ORIENTED_EDGE('',*,*,#504,.T.);
#506=CARTESIAN_POINT('',(1.36832013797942,0.790000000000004,0.));
#507=DIRECTION('',(0.,0.,1.));
#508=DIRECTION('',(1.,0.,0.));
#509=AXIS2_PLACEMENT_3D('',#506,#507,#508);
#510=CIRCLE('',#509,0.395);
#511=CARTESIAN_POINT('',(1.63942782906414,0.502727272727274,0.));
#512=VERTEX_POINT('',#511);
#513=EDGE_CURVE('E519',#512,#503,#510,.T.);
#514=ORIENTED_EDGE('',*,*,#513,.F.);
#515=CARTESIAN_POINT('',(2.11386628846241,0.,0.));
#516=DIRECTION('',(0.,0.,1.));
#517=DIRECTION('',(1.,0.,0.));
#518=AXIS2_PLACEMENT_3D('',#515,#516,#517);
#519=CIRCLE('',#518,0.69125);
#520=CARTESIAN_POINT('',(1.63942782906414,-0.502727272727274,0.));
#521=VERTEX_POINT('',#520);
#522=EDGE_CURVE('E378',#512,#521,#519,.T.);
#523=ORIENTED_EDGE('',*,*,#522,.T.);
#524=CARTESIAN_POINT('',(1.36832013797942,-0.790000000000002,0.));
#525=DIRECTION('',(0.,0.,1.));
#526=DIRECTION('',(1.,0.,0.));
#527=AXIS2_PLACEMENT_3D('',#524,#525,#526);
#528=CIRCLE('',#527,0.395);
#529=CARTESIAN_POINT('',(1.25508850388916,-1.16842251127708,0.));
#530=VERTEX_POINT('',#529);
#531=EDGE_CURVE('E366',#530,#521,#528,.T.);
#532=ORIENTED_EDGE('',*,*,#531,.F.);
#533=CARTESIAN_POINT('',(1.05693314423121,-1.83066190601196,0.));
#534=DIRECTION('',(0.,0.,1.));
#535=DIRECTION('',(1.,0.,0.));
#536=AXIS2_PLACEMENT_3D('',#533,#534,#535);
#537=CIRCLE('',#536,0.69125);
#538=CARTESIAN_POINT('',(0.384339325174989,-1.67114978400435,0.));
#539=VERTEX_POINT('',#538);
#540=EDGE_CURVE('E323',#530,#539,#537,.T.);
#541=ORIENTED_EDGE('',*,*,#540,.T.);
#542=CARTESIAN_POINT('',(0.,-1.58,0.));
#543=DIRECTION('',(0.,0.,1.));
#544=DIRECTION('',(1.,0.,0.));
#545=AXIS2_PLACEMENT_3D('',#542,#543,#544);
#546=CIRCLE('',#545,0.395);
#547=CARTESIAN_POINT('',(-0.384339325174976,-1.67114978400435,0.));
#548=VERTEX_POINT('',#547);
#549=EDGE_CURVE('E353',#548,#539,#546,.T.);
#550=ORIENTED_EDGE('',*,*,#549,.F.);
#551=CARTESIAN_POINT('',(-1.0569331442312,-1.83066190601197,0.));
#552=DIRECTION('',(0.,0.,1.));
#553=DIRECTION('',(1.,0.,0.));
#554=AXIS2_PLACEMENT_3D('',#551,#552,#553);
#555=CIRCLE('',#554,0.69125);
#556=CARTESIAN_POINT('',(-1.25508850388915,-1.16842251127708,0.));
#557=VERTEX_POINT('',#556);
#558=EDGE_CURVE('E294',#548,#557,#555,.T.);
#559=ORIENTED_EDGE('',*,*,#558,.T.);
#560=CARTESIAN_POINT('',(-1.36832013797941,-0.790000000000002,0.));
#561=DIRECTION('',(0.,0.,1.));
#562=DIRECTION('',(1.,0.,0.));
#563=AXIS2_PLACEMENT_3D('',#560,#561,#562);
#564=CIRCLE('',#563,0.395);
#565=CARTESIAN_POINT('',(-1.63942782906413,-0.502727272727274,0.));
#566=VERTEX_POINT('',#565);
#567=EDGE_CURVE('E292',#566,#557,#564,.T.);
#568=ORIENTED_EDGE('',*,*,#567,.F.);
#569=CARTESIAN_POINT('',(-2.1138662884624,0.,0.));
#570=DIRECTION('',(0.,0.,1.));
#571=DIRECTION('',(1.,0.,0.));
#572=AXIS2_PLACEMENT_3D('',#569,#570,#571);
#573=CIRCLE('',#572,0.69125);
#574=EDGE_CURVE('E491',#566,#476,#573,.T.);
#575=ORIENTED_EDGE('',*,*,#574,.T.);
#576=EDGE_LOOP('',(#478,#487,#496,#505,#514,#523,#532,#541,#550,#559,#568,#575));
#577=FACE_BOUND('',#576,.T.);
#578=CARTESIAN_POINT('',(0.,0.,0.));
#579=DIRECTION('',(0.,0.,-1.));
#580=DIRECTION('',(-1.,0.,0.));
#581=AXIS2_PLACEMENT_3D('',#578,#579,#580);
#582=CIRCLE('',#581,4.51);
#583=CARTESIAN_POINT('',(-4.51,0.,0.));
#584=VERTEX_POINT('',#583);
#585=EDGE_CURVE('E12',#584,#584,#582,.T.);
#586=ORIENTED_EDGE('',*,*,#585,.F.);
#587=EDGE_LOOP('',(#586));
#588=FACE_BOUND('',#587,.T.);
#589=ADVANCED_FACE('F184',(#577,#588),#467,.T.);
#590=CARTESIAN_POINT('',(0.,0.,0.));
#591=DIRECTION('',(0.,0.,-1.));
#592=DIRECTION('',(-1.,0.,0.));
#593=AXIS2_PLACEMENT_3D('',#590,#591,#592);
#594=CYLINDRICAL_SURFACE('',#593,4.51);
#595=ORIENTED_EDGE('',*,*,#585,.T.);
#596=EDGE_LOOP('',(#595));
#597=FACE_BOUND('',#596,.T.);
#598=CARTESIAN_POINT('',(0.,0.,-0.500000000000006));
#599=DIRECTION('',(0.,0.,-1.));
#600=DIRECTION('',(-1.,0.,0.));
#601=AXIS2_PLACEMENT_3D('',#598,#599,#600);
#602=CIRCLE('',#601,4.51);
#603=CARTESIAN_POINT('',(-4.51,0.,-0.500000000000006));
#604=VERTEX_POINT('',#603);
#605=EDGE_CURVE('E190',#604,#604,#602,.T.);
#606=ORIENTED_EDGE('',*,*,#605,.F.);
#607=EDGE_LOOP('',(#606));
#608=FACE_BOUND('',#607,.T.);
#609=ADVANCED_FACE('F476',(#597,#608),#594,.T.);
#610=CARTESIAN_POINT('',(0.,0.,-3.01));
#611=DIRECTION('',(0.,0.,1.));
#612=DIRECTION('',(1.,0.,0.));
#613=AXIS2_PLACEMENT_3D('',#610,#611,#612);
#614=CONICAL_SURFACE('',#613,2.,0.78539816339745);
#615=ORIENTED_EDGE('',*,*,#605,.T.);
#616=EDGE_LOOP('',(#615));
#617=FACE_BOUND('',#616,.T.);
#618=CARTESIAN_POINT('',(0.,0.,-3.01));
#619=DIRECTION('',(0.,0.,-1.));
#620=DIRECTION('',(-1.,0.,0.));
#621=AXIS2_PLACEMENT_3D('',#618,#619,#620);
#622=CIRCLE('',#621,2.);
#623=CARTESIAN_POINT('',(-2.,0.,-3.01));
#624=VERTEX_POINT('',#623);
#625=EDGE_CURVE('E487',#624,#624,#622,.T.);
#626=ORIENTED_EDGE('',*,*,#625,.F.);
#627=EDGE_LOOP('',(#626));
#628=FACE_BOUND('',#627,.T.);
#629=ADVANCED_FACE('F473',(#617,#628),#614,.T.);
#630=CARTESIAN_POINT('',(0.,0.,0.));
#631=DIRECTION('',(0.,0.,-1.));
#632=DIRECTION('',(-1.,0.,0.));
#633=AXIS2_PLACEMENT_3D('',#630,#631,#632);
#634=CYLINDRICAL_SURFACE('',#633,2.);
#635=CARTESIAN_POINT('',(0.,0.,-11.774833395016));
#636=DIRECTION('',(0.,0.,-1.));
#637=DIRECTION('',(0.,1.,0.));
#638=AXIS2_PLACEMENT_3D('',#635,#636,#637);
#639=CIRCLE('',#638,2.);
#640=CARTESIAN_POINT('',(0.,2.,-11.774833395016));
#641=VERTEX_POINT('',#640);
#642=EDGE_CURVE('E692',#641,#641,#639,.T.);
#643=ORIENTED_EDGE('',*,*,#642,.F.);
#644=EDGE_LOOP('',(#643));
#645=FACE_BOUND('',#644,.T.);
#646=ORIENTED_EDGE('',*,*,#625,.T.);
#647=EDGE_LOOP('',(#646));
#648=FACE_BOUND('',#647,.T.);
#649=ADVANCED_FACE('F462',(#645,#648),#634,.T.);
#650=CARTESIAN_POINT('',(-1.36832013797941,0.790000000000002,-500000.));
#651=DIRECTION('',(0.,0.,1.));
#652=DIRECTION('',(1.,0.,0.));
#653=AXIS2_PLACEMENT_3D('',#650,#651,#652);
#654=CYLINDRICAL_SURFACE('',#653,0.395);
#655=ORIENTED_EDGE('',*,*,#388,.F.);
#656=DIRECTION('',(0.,0.,1.));
#657=VECTOR('',#656,1.);
#658=CARTESIAN_POINT('',(-1.25508850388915,1.16842251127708,-500000.));
#659=LINE('',#658,#657);
#660=EDGE_CURVE('E503',#346,#474,#659,.T.);
#661=ORIENTED_EDGE('',*,*,#660,.T.);
#662=ORIENTED_EDGE('',*,*,#477,.T.);
#663=DIRECTION('',(0.,0.,1.));
#664=VECTOR('',#663,1.);
#665=CARTESIAN_POINT('',(-1.63942782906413,0.502727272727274,-500000.));
#666=LINE('',#665,#664);
#667=EDGE_CURVE('E457',#387,#476,#666,.T.);
#668=ORIENTED_EDGE('',*,*,#667,.F.);
#669=EDGE_LOOP('',(#655,#661,#662,#668));
#670=FACE_BOUND('',#669,.T.);
#671=ADVANCED_FACE('F463',(#670),#654,.F.);
#672=CARTESIAN_POINT('',(-2.1138662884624,0.,-500000.));
#673=DIRECTION('',(0.,0.,1.));
#674=DIRECTION('',(1.,0.,0.));
#675=AXIS2_PLACEMENT_3D('',#672,#673,#674);
#676=CYLINDRICAL_SURFACE('',#675,0.69125);
#677=DIRECTION('',(0.,0.,1.));
#678=VECTOR('',#677,1.);
#679=CARTESIAN_POINT('',(-1.63942782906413,-0.502727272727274,-500000.));
#680=LINE('',#679,#678);
#681=EDGE_CURVE('E495',#418,#566,#680,.T.);
#682=ORIENTED_EDGE('',*,*,#681,.F.);
#683=ORIENTED_EDGE('',*,*,#419,.T.);
#684=ORIENTED_EDGE('',*,*,#667,.T.);
#685=ORIENTED_EDGE('',*,*,#574,.F.);
#686=EDGE_LOOP('',(#682,#683,#684,#685));
#687=FACE_BOUND('',#686,.T.);
#688=ADVANCED_FACE('F442',(#687),#676,.T.);
#689=CARTESIAN_POINT('',(-1.36832013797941,-0.790000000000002,-500000.));
#690=DIRECTION('',(0.,0.,1.));
#691=DIRECTION('',(1.,0.,0.));
#692=AXIS2_PLACEMENT_3D('',#689,#690,#691);
#693=CYLINDRICAL_SURFACE('',#692,0.395);
#694=ORIENTED_EDGE('',*,*,#458,.F.);
#695=ORIENTED_EDGE('',*,*,#681,.T.);
#696=ORIENTED_EDGE('',*,*,#567,.T.);
#697=DIRECTION('',(0.,0.,1.));
#698=VECTOR('',#697,1.);
#699=CARTESIAN_POINT('',(-1.25508850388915,-1.16842251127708,-500000.));
#700=LINE('',#699,#698);
#701=EDGE_CURVE('E284',#58,#557,#700,.T.);
#702=ORIENTED_EDGE('',*,*,#701,.F.);
#703=EDGE_LOOP('',(#694,#695,#696,#702));
#704=FACE_BOUND('',#703,.T.);
#705=ADVANCED_FACE('F290',(#704),#693,.F.);
#706=CARTESIAN_POINT('',(-1.0569331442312,1.83066190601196,-500000.));
#707=DIRECTION('',(0.,0.,1.));
#708=DIRECTION('',(1.,0.,0.));
#709=AXIS2_PLACEMENT_3D('',#706,#707,#708);
#710=CYLINDRICAL_SURFACE('',#709,0.69125);
#711=ORIENTED_EDGE('',*,*,#660,.F.);
#712=ORIENTED_EDGE('',*,*,#347,.T.);
#713=DIRECTION('',(0.,0.,1.));
#714=VECTOR('',#713,1.);
#715=CARTESIAN_POINT('',(-0.384339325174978,1.67114978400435,-500000.));
#716=LINE('',#715,#714);
#717=EDGE_CURVE('E430',#315,#485,#716,.T.);
#718=ORIENTED_EDGE('',*,*,#717,.T.);
#719=ORIENTED_EDGE('',*,*,#486,.F.);
#720=EDGE_LOOP('',(#711,#712,#718,#719));
#721=FACE_BOUND('',#720,.T.);
#722=ADVANCED_FACE('F417',(#721),#710,.T.);
#723=CARTESIAN_POINT('',(0.,1.58,-500000.));
#724=DIRECTION('',(0.,0.,1.));
#725=DIRECTION('',(1.,0.,0.));
#726=AXIS2_PLACEMENT_3D('',#723,#724,#725);
#727=CYLINDRICAL_SURFACE('',#726,0.395);
#728=ORIENTED_EDGE('',*,*,#316,.F.);
#729=DIRECTION('',(0.,0.,1.));
#730=VECTOR('',#729,1.);
#731=CARTESIAN_POINT('',(0.384339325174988,1.67114978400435,-500000.));
#732=LINE('',#731,#730);
#733=EDGE_CURVE('E514',#274,#494,#732,.T.);
#734=ORIENTED_EDGE('',*,*,#733,.T.);
#735=ORIENTED_EDGE('',*,*,#495,.T.);
#736=ORIENTED_EDGE('',*,*,#717,.F.);
#737=EDGE_LOOP('',(#728,#734,#735,#736));
#738=FACE_BOUND('',#737,.T.);
#739=ADVANCED_FACE('F395',(#738),#727,.F.);
#740=CARTESIAN_POINT('',(1.05693314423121,1.83066190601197,-500000.));
#741=DIRECTION('',(0.,0.,1.));
#742=DIRECTION('',(1.,0.,0.));
#743=AXIS2_PLACEMENT_3D('',#740,#741,#742);
#744=CYLINDRICAL_SURFACE('',#743,0.69125);
#745=ORIENTED_EDGE('',*,*,#733,.F.);
#746=ORIENTED_EDGE('',*,*,#275,.T.);
#747=DIRECTION('',(0.,0.,1.));
#748=VECTOR('',#747,1.);
#749=CARTESIAN_POINT('',(1.25508850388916,1.16842251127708,-500000.));
#750=LINE('',#749,#748);
#751=EDGE_CURVE('E405',#243,#503,#750,.T.);
#752=ORIENTED_EDGE('',*,*,#751,.T.);
#753=ORIENTED_EDGE('',*,*,#504,.F.);
#754=EDGE_LOOP('',(#745,#746,#752,#753));
#755=FACE_BOUND('',#754,.T.);
#756=ADVANCED_FACE('F390',(#755),#744,.T.);
#757=CARTESIAN_POINT('',(1.36832013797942,0.790000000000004,-500000.));
#758=DIRECTION('',(0.,0.,1.));
#759=DIRECTION('',(1.,0.,0.));
#760=AXIS2_PLACEMENT_3D('',#757,#758,#759);
#761=CYLINDRICAL_SURFACE('',#760,0.395);
#762=ORIENTED_EDGE('',*,*,#244,.F.);
#763=DIRECTION('',(0.,0.,1.));
#764=VECTOR('',#763,1.);
#765=CARTESIAN_POINT('',(1.63942782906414,0.502727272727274,-500000.));
#766=LINE('',#765,#764);
#767=EDGE_CURVE('E372',#202,#512,#766,.T.);
#768=ORIENTED_EDGE('',*,*,#767,.T.);
#769=ORIENTED_EDGE('',*,*,#513,.T.);
#770=ORIENTED_EDGE('',*,*,#751,.F.);
#771=EDGE_LOOP('',(#762,#768,#769,#770));
#772=FACE_BOUND('',#771,.T.);
#773=ADVANCED_FACE('F394',(#772),#761,.F.);
#774=CARTESIAN_POINT('',(2.11386628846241,0.,-500000.));
#775=DIRECTION('',(0.,0.,1.));
#776=DIRECTION('',(1.,0.,0.));
#777=AXIS2_PLACEMENT_3D('',#774,#775,#776);
#778=CYLINDRICAL_SURFACE('',#777,0.69125);
#779=ORIENTED_EDGE('',*,*,#767,.F.);
#780=ORIENTED_EDGE('',*,*,#203,.T.);
#781=DIRECTION('',(0.,0.,1.));
#782=VECTOR('',#781,1.);
#783=CARTESIAN_POINT('',(1.63942782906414,-0.502727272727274,-500000.));
#784=LINE('',#783,#782);
#785=EDGE_CURVE('E367',#171,#521,#784,.T.);
#786=ORIENTED_EDGE('',*,*,#785,.T.);
#787=ORIENTED_EDGE('',*,*,#522,.F.);
#788=EDGE_LOOP('',(#779,#780,#786,#787));
#789=FACE_BOUND('',#788,.T.);
#790=ADVANCED_FACE('F313',(#789),#778,.T.);
#791=CARTESIAN_POINT('',(1.36832013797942,-0.790000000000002,-500000.));
#792=DIRECTION('',(0.,0.,1.));
#793=DIRECTION('',(1.,0.,0.));
#794=AXIS2_PLACEMENT_3D('',#791,#792,#793);
#795=CYLINDRICAL_SURFACE('',#794,0.395);
#796=ORIENTED_EDGE('',*,*,#172,.F.);
#797=DIRECTION('',(0.,0.,1.));
#798=VECTOR('',#797,1.);
#799=CARTESIAN_POINT('',(1.25508850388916,-1.16842251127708,-500000.));
#800=LINE('',#799,#798);
#801=EDGE_CURVE('E357',#130,#530,#800,.T.);
#802=ORIENTED_EDGE('',*,*,#801,.T.);
#803=ORIENTED_EDGE('',*,*,#531,.T.);
#804=ORIENTED_EDGE('',*,*,#785,.F.);
#805=EDGE_LOOP('',(#796,#802,#803,#804));
#806=FACE_BOUND('',#805,.T.);
#807=ADVANCED_FACE('F335',(#806),#795,.F.);
#808=CARTESIAN_POINT('',(1.05693314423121,-1.83066190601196,-500000.));
#809=DIRECTION('',(0.,0.,1.));
#810=DIRECTION('',(1.,0.,0.));
#811=AXIS2_PLACEMENT_3D('',#808,#809,#810);
#812=CYLINDRICAL_SURFACE('',#811,0.69125);
#813=ORIENTED_EDGE('',*,*,#801,.F.);
#814=ORIENTED_EDGE('',*,*,#131,.T.);
#815=DIRECTION('',(0.,0.,1.));
#816=VECTOR('',#815,1.);
#817=CARTESIAN_POINT('',(0.384339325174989,-1.67114978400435,-500000.));
#818=LINE('',#817,#816);
#819=EDGE_CURVE('E306',#99,#539,#818,.T.);
#820=ORIENTED_EDGE('',*,*,#819,.T.);
#821=ORIENTED_EDGE('',*,*,#540,.F.);
#822=EDGE_LOOP('',(#813,#814,#820,#821));
#823=FACE_BOUND('',#822,.T.);
#824=ADVANCED_FACE('F331',(#823),#812,.T.);
#825=CARTESIAN_POINT('',(0.,-1.58,-500000.));
#826=DIRECTION('',(0.,0.,1.));
#827=DIRECTION('',(1.,0.,0.));
#828=AXIS2_PLACEMENT_3D('',#825,#826,#827);
#829=CYLINDRICAL_SURFACE('',#828,0.395);
#830=ORIENTED_EDGE('',*,*,#100,.F.);
#831=DIRECTION('',(0.,0.,1.));
#832=VECTOR('',#831,1.);
#833=CARTESIAN_POINT('',(-0.384339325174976,-1.67114978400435,-500000.));
#834=LINE('',#833,#832);
#835=EDGE_CURVE('E287',#56,#548,#834,.T.);
#836=ORIENTED_EDGE('',*,*,#835,.T.);
#837=ORIENTED_EDGE('',*,*,#549,.T.);
#838=ORIENTED_EDGE('',*,*,#819,.F.);
#839=EDGE_LOOP('',(#830,#836,#837,#838));
#840=FACE_BOUND('',#839,.T.);
#841=ADVANCED_FACE('F308',(#840),#829,.F.);
#842=CARTESIAN_POINT('',(-1.0569331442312,-1.83066190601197,-500000.));
#843=DIRECTION('',(0.,0.,1.));
#844=DIRECTION('',(1.,0.,0.));
#845=AXIS2_PLACEMENT_3D('',#842,#843,#844);
#846=CYLINDRICAL_SURFACE('',#845,0.69125);
#847=ORIENTED_EDGE('',*,*,#835,.F.);
#848=ORIENTED_EDGE('',*,*,#59,.T.);
#849=ORIENTED_EDGE('',*,*,#701,.T.);
#850=ORIENTED_EDGE('',*,*,#558,.F.);
#851=EDGE_LOOP('',(#847,#848,#849,#850));
#852=FACE_BOUND('',#851,.T.);
#853=ADVANCED_FACE('F282',(#852),#846,.T.);
#854=CARTESIAN_POINT('',(0.,0.,-11.774833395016));
#855=DIRECTION('',(0.,0.,1.));
#856=DIRECTION('',(0.,-1.,0.));
#857=AXIS2_PLACEMENT_3D('',#854,#855,#856);
#858=CONICAL_SURFACE('',#857,2.,1.0471975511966);
#859=CARTESIAN_POINT('',(0.,0.,-12.));
#860=DIRECTION('',(0.,0.,-1.));
#861=DIRECTION('',(0.,1.,0.));
#862=AXIS2_PLACEMENT_3D('',#859,#860,#861);
#863=CIRCLE('',#862,1.61);
#864=CARTESIAN_POINT('',(0.,1.61,-12.));
#865=VERTEX_POINT('',#864);
#866=EDGE_CURVE('E288',#865,#865,#863,.T.);
#867=ORIENTED_EDGE('',*,*,#866,.F.);
#868=EDGE_LOOP('',(#867));
#869=FACE_BOUND('',#868,.T.);
#870=ORIENTED_EDGE('',*,*,#642,.T.);
#871=EDGE_LOOP('',(#870));
#872=FACE_BOUND('',#871,.T.);
#873=ADVANCED_FACE('F340',(#869,#872),#858,.T.);
#874=CARTESIAN_POINT('',(0.,2.,-12.));
#875=DIRECTION('',(0.,0.,-1.));
#876=DIRECTION('',(-1.,0.,0.));
#877=AXIS2_PLACEMENT_3D('',#874,#875,#876);
#878=PLANE('',#877);
#879=ORIENTED_EDGE('',*,*,#866,.T.);
#880=EDGE_LOOP('',(#879));
#881=FACE_BOUND('',#880,.T.);
#882=ADVANCED_FACE('F467',(#881),#878,.T.);
#883=CLOSED_SHELL('',(#462,#589,#609,#629,#649,#671,#688,#705,#722,#739,#756,#773,#790,#807,
#824,#841,#853,#873,#882));
#884=MANIFOLD_SOLID_BREP('B2',#883);
#885=ADVANCED_BREP_SHAPE_REPRESENTATION('',(#18,#884),#14);
#886=SHAPE_DEFINITION_REPRESENTATION(#9,#885);
ENDSEC;
END-ISO-10303-21;
